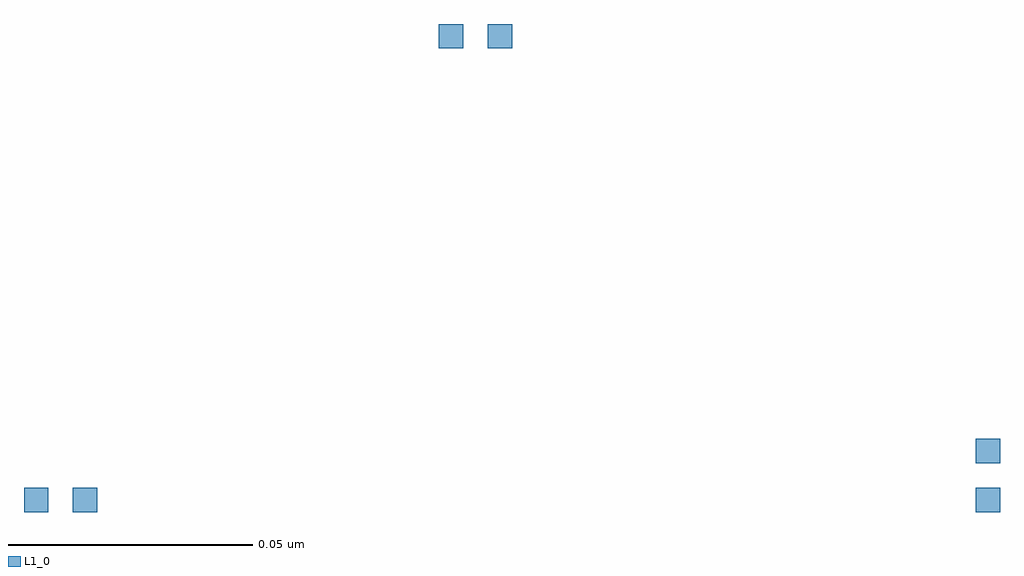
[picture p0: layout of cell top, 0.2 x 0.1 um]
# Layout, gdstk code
from math import pi, radians
import gdstk
lib = gdstk.Library(unit=1e-6, precision=1e-09)
def R(c, l, rs):  # rectangles x0, y0, x1, y1
    for r in rs: c.add(gdstk.rectangle(r[:2], r[2:], *l))
L1_0 = (1, 0)

leaf = lib.new_cell('leaf')
R(leaf, L1_0, [(0,0,0.005,0.005)])

mid = lib.new_cell('mid')
mid.add(gdstk.Reference(leaf, (0,0)))
mid.add(gdstk.Reference(leaf, (0.01,0)))

top = lib.new_cell('top')
top.add(gdstk.Reference(mid, (0,0)))
top.add(gdstk.Reference(mid, (0.1,0.1), rotation=pi))
top.add(gdstk.Reference(mid, (0.2,0), rotation=pi/2))

lib.write_gds('top.gds')
